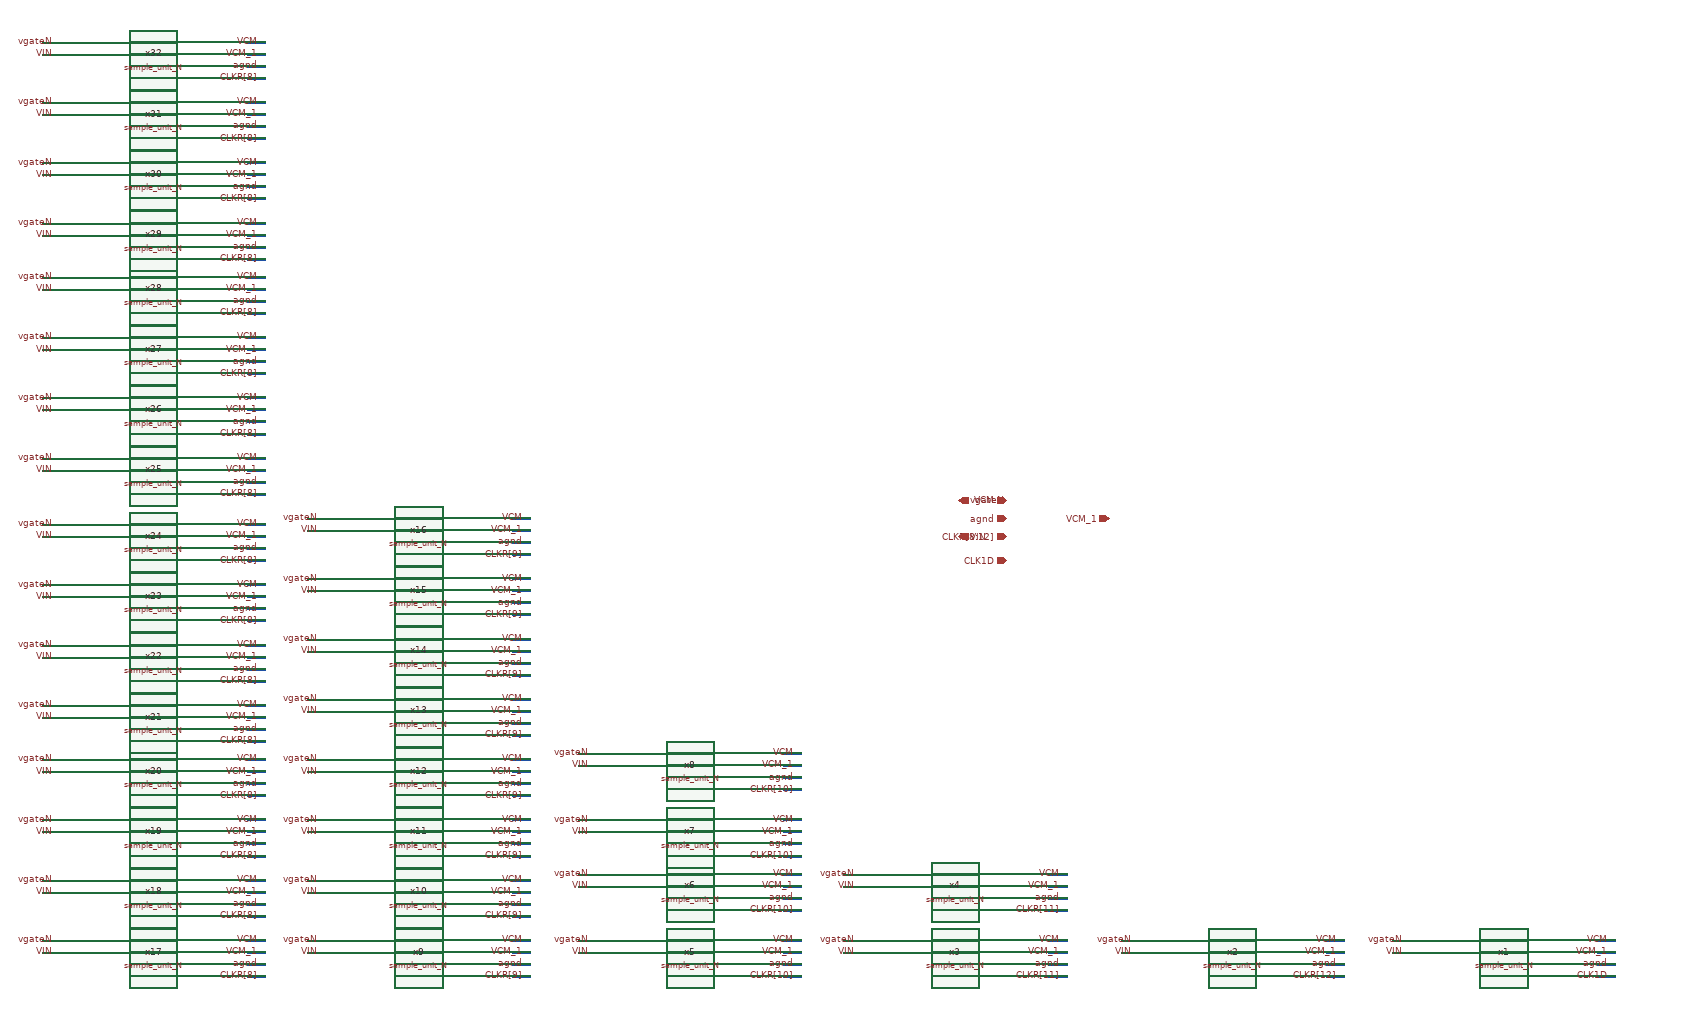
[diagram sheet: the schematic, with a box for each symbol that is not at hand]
v {xschem version=3.1.0 file_version=1.2
}
G {}
K {}
V {}
S {}
E {}
N 1610 -1050 1650 -1050 {
lab=vgateN}
N 1610 -1030 1650 -1030 {
lab=VIN}
N 1950 -1050 1980 -1050 {
lab=VCM}
N 1950 -1030 1980 -1030 {
lab=VCM_1}
N 1950 -1010 1980 -1010 {
lab=agnd}
N 1950 -990 1980 -990 {
lab=CLK1D}
N 1160 -1050 1200 -1050 {
lab=vgateN}
N 1160 -1030 1200 -1030 {
lab=VIN}
N 1500 -1050 1530 -1050 {
lab=VCM}
N 1500 -1030 1530 -1030 {
lab=VCM_1}
N 1500 -1010 1530 -1010 {
lab=agnd}
N 1500 -990 1530 -990 {
lab=CLKR[12]}
N 700 -1050 740 -1050 {
lab=vgateN}
N 700 -1030 740 -1030 {
lab=VIN}
N 1040 -1050 1070 -1050 {
lab=VCM}
N 1040 -1030 1070 -1030 {
lab=VCM_1}
N 1040 -1010 1070 -1010 {
lab=agnd}
N 1040 -990 1070 -990 {
lab=CLKR[11]}
N 700 -1160 740 -1160 {
lab=vgateN}
N 700 -1140 740 -1140 {
lab=VIN}
N 1040 -1160 1070 -1160 {
lab=VCM}
N 1040 -1140 1070 -1140 {
lab=VCM_1}
N 1040 -1120 1070 -1120 {
lab=agnd}
N 1040 -1100 1070 -1100 {
lab=CLKR[11]}
N 260 -1050 300 -1050 {
lab=vgateN}
N 260 -1030 300 -1030 {
lab=VIN}
N 600 -1050 630 -1050 {
lab=VCM}
N 600 -1030 630 -1030 {
lab=VCM_1}
N 600 -1010 630 -1010 {
lab=agnd}
N 600 -990 630 -990 {
lab=CLKR[10]}
N 260 -1160 300 -1160 {
lab=vgateN}
N 260 -1140 300 -1140 {
lab=VIN}
N 600 -1160 630 -1160 {
lab=VCM}
N 600 -1140 630 -1140 {
lab=VCM_1}
N 600 -1120 630 -1120 {
lab=agnd}
N 600 -1100 630 -1100 {
lab=CLKR[10]}
N 260 -1250 300 -1250 {
lab=vgateN}
N 260 -1230 300 -1230 {
lab=VIN}
N 600 -1250 630 -1250 {
lab=VCM}
N 600 -1230 630 -1230 {
lab=VCM_1}
N 600 -1210 630 -1210 {
lab=agnd}
N 600 -1190 630 -1190 {
lab=CLKR[10]}
N 260 -1360 300 -1360 {
lab=vgateN}
N 260 -1340 300 -1340 {
lab=VIN}
N 600 -1360 630 -1360 {
lab=VCM}
N 600 -1340 630 -1340 {
lab=VCM_1}
N 600 -1320 630 -1320 {
lab=agnd}
N 600 -1300 630 -1300 {
lab=CLKR[10]}
N -190 -1050 -150 -1050 {
lab=vgateN}
N -190 -1030 -150 -1030 {
lab=VIN}
N 150 -1050 180 -1050 {
lab=VCM}
N 150 -1030 180 -1030 {
lab=VCM_1}
N 150 -1010 180 -1010 {
lab=agnd}
N 150 -990 180 -990 {
lab=CLKR[9]}
N -190 -1150 -150 -1150 {
lab=vgateN}
N -190 -1130 -150 -1130 {
lab=VIN}
N 150 -1150 180 -1150 {
lab=VCM}
N 150 -1130 180 -1130 {
lab=VCM_1}
N 150 -1110 180 -1110 {
lab=agnd}
N 150 -1090 180 -1090 {
lab=CLKR[9]}
N -190 -1250 -150 -1250 {
lab=vgateN}
N -190 -1230 -150 -1230 {
lab=VIN}
N 150 -1250 180 -1250 {
lab=VCM}
N 150 -1230 180 -1230 {
lab=VCM_1}
N 150 -1210 180 -1210 {
lab=agnd}
N 150 -1190 180 -1190 {
lab=CLKR[9]}
N -190 -1350 -150 -1350 {
lab=vgateN}
N -190 -1330 -150 -1330 {
lab=VIN}
N 150 -1350 180 -1350 {
lab=VCM}
N 150 -1330 180 -1330 {
lab=VCM_1}
N 150 -1310 180 -1310 {
lab=agnd}
N 150 -1290 180 -1290 {
lab=CLKR[9]}
N -190 -1450 -150 -1450 {
lab=vgateN}
N -190 -1430 -150 -1430 {
lab=VIN}
N 150 -1450 180 -1450 {
lab=VCM}
N 150 -1430 180 -1430 {
lab=VCM_1}
N 150 -1410 180 -1410 {
lab=agnd}
N 150 -1390 180 -1390 {
lab=CLKR[9]}
N -190 -1550 -150 -1550 {
lab=vgateN}
N -190 -1530 -150 -1530 {
lab=VIN}
N 150 -1550 180 -1550 {
lab=VCM}
N 150 -1530 180 -1530 {
lab=VCM_1}
N 150 -1510 180 -1510 {
lab=agnd}
N 150 -1490 180 -1490 {
lab=CLKR[9]}
N -190 -1650 -150 -1650 {
lab=vgateN}
N -190 -1630 -150 -1630 {
lab=VIN}
N 150 -1650 180 -1650 {
lab=VCM}
N 150 -1630 180 -1630 {
lab=VCM_1}
N 150 -1610 180 -1610 {
lab=agnd}
N 150 -1590 180 -1590 {
lab=CLKR[9]}
N -190 -1750 -150 -1750 {
lab=vgateN}
N -190 -1730 -150 -1730 {
lab=VIN}
N 150 -1750 180 -1750 {
lab=VCM}
N 150 -1730 180 -1730 {
lab=VCM_1}
N 150 -1710 180 -1710 {
lab=agnd}
N 150 -1690 180 -1690 {
lab=CLKR[9]}
N -630 -1050 -590 -1050 {
lab=vgateN}
N -630 -1030 -590 -1030 {
lab=VIN}
N -290 -1050 -260 -1050 {
lab=VCM}
N -290 -1030 -260 -1030 {
lab=VCM_1}
N -290 -1010 -260 -1010 {
lab=agnd}
N -290 -990 -260 -990 {
lab=CLKR[9]}
N -630 -1150 -590 -1150 {
lab=vgateN}
N -630 -1130 -590 -1130 {
lab=VIN}
N -290 -1150 -260 -1150 {
lab=VCM}
N -290 -1130 -260 -1130 {
lab=VCM_1}
N -290 -1110 -260 -1110 {
lab=agnd}
N -290 -1090 -260 -1090 {
lab=CLKR[9]}
N -630 -1250 -590 -1250 {
lab=vgateN}
N -630 -1230 -590 -1230 {
lab=VIN}
N -290 -1250 -260 -1250 {
lab=VCM}
N -290 -1230 -260 -1230 {
lab=VCM_1}
N -290 -1210 -260 -1210 {
lab=agnd}
N -290 -1190 -260 -1190 {
lab=CLKR[9]}
N -630 -1350 -590 -1350 {
lab=vgateN}
N -630 -1330 -590 -1330 {
lab=VIN}
N -290 -1350 -260 -1350 {
lab=VCM}
N -290 -1330 -260 -1330 {
lab=VCM_1}
N -290 -1310 -260 -1310 {
lab=agnd}
N -290 -1290 -260 -1290 {
lab=CLKR[9]}
N -630 -1440 -590 -1440 {
lab=vgateN}
N -630 -1420 -590 -1420 {
lab=VIN}
N -290 -1440 -260 -1440 {
lab=VCM}
N -290 -1420 -260 -1420 {
lab=VCM_1}
N -290 -1400 -260 -1400 {
lab=agnd}
N -290 -1380 -260 -1380 {
lab=CLKR[9]}
N -630 -1540 -590 -1540 {
lab=vgateN}
N -630 -1520 -590 -1520 {
lab=VIN}
N -290 -1540 -260 -1540 {
lab=VCM}
N -290 -1520 -260 -1520 {
lab=VCM_1}
N -290 -1500 -260 -1500 {
lab=agnd}
N -290 -1480 -260 -1480 {
lab=CLKR[9]}
N -630 -1640 -590 -1640 {
lab=vgateN}
N -630 -1620 -590 -1620 {
lab=VIN}
N -290 -1640 -260 -1640 {
lab=VCM}
N -290 -1620 -260 -1620 {
lab=VCM_1}
N -290 -1600 -260 -1600 {
lab=agnd}
N -290 -1580 -260 -1580 {
lab=CLKR[9]}
N -630 -1740 -590 -1740 {
lab=vgateN}
N -630 -1720 -590 -1720 {
lab=VIN}
N -290 -1740 -260 -1740 {
lab=VCM}
N -290 -1720 -260 -1720 {
lab=VCM_1}
N -290 -1700 -260 -1700 {
lab=agnd}
N -290 -1680 -260 -1680 {
lab=CLKR[9]}
N -630 -1850 -590 -1850 {
lab=vgateN}
N -630 -1830 -590 -1830 {
lab=VIN}
N -290 -1850 -260 -1850 {
lab=VCM}
N -290 -1830 -260 -1830 {
lab=VCM_1}
N -290 -1810 -260 -1810 {
lab=agnd}
N -290 -1790 -260 -1790 {
lab=CLKR[9]}
N -630 -1950 -590 -1950 {
lab=vgateN}
N -630 -1930 -590 -1930 {
lab=VIN}
N -290 -1950 -260 -1950 {
lab=VCM}
N -290 -1930 -260 -1930 {
lab=VCM_1}
N -290 -1910 -260 -1910 {
lab=agnd}
N -290 -1890 -260 -1890 {
lab=CLKR[9]}
N -630 -2050 -590 -2050 {
lab=vgateN}
N -630 -2030 -590 -2030 {
lab=VIN}
N -290 -2050 -260 -2050 {
lab=VCM}
N -290 -2030 -260 -2030 {
lab=VCM_1}
N -290 -2010 -260 -2010 {
lab=agnd}
N -290 -1990 -260 -1990 {
lab=CLKR[9]}
N -630 -2150 -590 -2150 {
lab=vgateN}
N -630 -2130 -590 -2130 {
lab=VIN}
N -290 -2150 -260 -2150 {
lab=VCM}
N -290 -2130 -260 -2130 {
lab=VCM_1}
N -290 -2110 -260 -2110 {
lab=agnd}
N -290 -2090 -260 -2090 {
lab=CLKR[9]}
N -630 -2240 -590 -2240 {
lab=vgateN}
N -630 -2220 -590 -2220 {
lab=VIN}
N -290 -2240 -260 -2240 {
lab=VCM}
N -290 -2220 -260 -2220 {
lab=VCM_1}
N -290 -2200 -260 -2200 {
lab=agnd}
N -290 -2180 -260 -2180 {
lab=CLKR[9]}
N -630 -2340 -590 -2340 {
lab=vgateN}
N -630 -2320 -590 -2320 {
lab=VIN}
N -290 -2340 -260 -2340 {
lab=VCM}
N -290 -2320 -260 -2320 {
lab=VCM_1}
N -290 -2300 -260 -2300 {
lab=agnd}
N -290 -2280 -260 -2280 {
lab=CLKR[9]}
N -630 -2440 -590 -2440 {
lab=vgateN}
N -630 -2420 -590 -2420 {
lab=VIN}
N -290 -2440 -260 -2440 {
lab=VCM}
N -290 -2420 -260 -2420 {
lab=VCM_1}
N -290 -2400 -260 -2400 {
lab=agnd}
N -290 -2380 -260 -2380 {
lab=CLKR[9]}
N -630 -2540 -590 -2540 {
lab=vgateN}
N -630 -2520 -590 -2520 {
lab=VIN}
N -290 -2540 -260 -2540 {
lab=VCM}
N -290 -2520 -260 -2520 {
lab=VCM_1}
N -290 -2500 -260 -2500 {
lab=agnd}
N -290 -2480 -260 -2480 {
lab=CLKR[9]}
C {/home/yihengfu/openmpw/tools-dev/sample_unit_N.sym} 1800 -1020 0 0 {name=x1}
C {lab_pin.sym} 1970 -1050 0 0 {name=p1 sig_type=std_logic lab=VCM}
C {lab_pin.sym} 1970 -1030 0 0 {name=p2 sig_type=std_logic lab=VCM_1}
C {lab_pin.sym} 1970 -1010 0 0 {name=p3 sig_type=std_logic lab=agnd}
C {lab_pin.sym} 1970 -990 0 0 {name=p4 sig_type=std_logic lab=CLK1D}
C {lab_pin.sym} 1630 -1050 0 0 {name=p5 sig_type=std_logic lab=vgateN}
C {lab_pin.sym} 1630 -1030 0 0 {name=p6 sig_type=std_logic lab=VIN}
C {/home/yihengfu/openmpw/tools-dev/sample_unit_N.sym} 1350 -1020 0 0 {name=x2}
C {lab_pin.sym} 1520 -1050 0 0 {name=p7 sig_type=std_logic lab=VCM}
C {lab_pin.sym} 1520 -1030 0 0 {name=p8 sig_type=std_logic lab=VCM_1}
C {lab_pin.sym} 1520 -1010 0 0 {name=p9 sig_type=std_logic lab=agnd}
C {lab_pin.sym} 1520 -990 0 0 {name=p10 sig_type=std_logic lab=CLKR[12]}
C {lab_pin.sym} 1180 -1050 0 0 {name=p11 sig_type=std_logic lab=vgateN}
C {lab_pin.sym} 1180 -1030 0 0 {name=p12 sig_type=std_logic lab=VIN}
C {/home/yihengfu/openmpw/tools-dev/sample_unit_N.sym} 890 -1020 0 0 {name=x3}
C {lab_pin.sym} 1060 -1050 0 0 {name=p13 sig_type=std_logic lab=VCM}
C {lab_pin.sym} 1060 -1030 0 0 {name=p14 sig_type=std_logic lab=VCM_1}
C {lab_pin.sym} 1060 -1010 0 0 {name=p15 sig_type=std_logic lab=agnd}
C {lab_pin.sym} 1060 -990 0 0 {name=p16 sig_type=std_logic lab=CLKR[11]}
C {lab_pin.sym} 720 -1050 0 0 {name=p17 sig_type=std_logic lab=vgateN}
C {lab_pin.sym} 720 -1030 0 0 {name=p18 sig_type=std_logic lab=VIN}
C {/home/yihengfu/openmpw/tools-dev/sample_unit_N.sym} 890 -1130 0 0 {name=x4}
C {lab_pin.sym} 1060 -1160 0 0 {name=p19 sig_type=std_logic lab=VCM}
C {lab_pin.sym} 1060 -1140 0 0 {name=p20 sig_type=std_logic lab=VCM_1}
C {lab_pin.sym} 1060 -1120 0 0 {name=p21 sig_type=std_logic lab=agnd}
C {lab_pin.sym} 1060 -1100 0 0 {name=p22 sig_type=std_logic lab=CLKR[11]}
C {lab_pin.sym} 720 -1160 0 0 {name=p23 sig_type=std_logic lab=vgateN}
C {lab_pin.sym} 720 -1140 0 0 {name=p24 sig_type=std_logic lab=VIN}
C {/home/yihengfu/openmpw/tools-dev/sample_unit_N.sym} 450 -1020 0 0 {name=x5}
C {lab_pin.sym} 620 -1050 0 0 {name=p25 sig_type=std_logic lab=VCM}
C {lab_pin.sym} 620 -1030 0 0 {name=p26 sig_type=std_logic lab=VCM_1}
C {lab_pin.sym} 620 -1010 0 0 {name=p27 sig_type=std_logic lab=agnd}
C {lab_pin.sym} 620 -990 0 0 {name=p28 sig_type=std_logic lab=CLKR[10]}
C {lab_pin.sym} 280 -1050 0 0 {name=p29 sig_type=std_logic lab=vgateN}
C {lab_pin.sym} 280 -1030 0 0 {name=p30 sig_type=std_logic lab=VIN}
C {/home/yihengfu/openmpw/tools-dev/sample_unit_N.sym} 450 -1130 0 0 {name=x6}
C {lab_pin.sym} 620 -1160 0 0 {name=p31 sig_type=std_logic lab=VCM}
C {lab_pin.sym} 620 -1140 0 0 {name=p32 sig_type=std_logic lab=VCM_1}
C {lab_pin.sym} 620 -1120 0 0 {name=p33 sig_type=std_logic lab=agnd}
C {lab_pin.sym} 620 -1100 0 0 {name=p34 sig_type=std_logic lab=CLKR[10]}
C {lab_pin.sym} 280 -1160 0 0 {name=p35 sig_type=std_logic lab=vgateN}
C {lab_pin.sym} 280 -1140 0 0 {name=p36 sig_type=std_logic lab=VIN}
C {/home/yihengfu/openmpw/tools-dev/sample_unit_N.sym} 450 -1220 0 0 {name=x7}
C {lab_pin.sym} 620 -1250 0 0 {name=p37 sig_type=std_logic lab=VCM}
C {lab_pin.sym} 620 -1230 0 0 {name=p38 sig_type=std_logic lab=VCM_1}
C {lab_pin.sym} 620 -1210 0 0 {name=p39 sig_type=std_logic lab=agnd}
C {lab_pin.sym} 620 -1190 0 0 {name=p40 sig_type=std_logic lab=CLKR[10]}
C {lab_pin.sym} 280 -1250 0 0 {name=p41 sig_type=std_logic lab=vgateN}
C {lab_pin.sym} 280 -1230 0 0 {name=p42 sig_type=std_logic lab=VIN}
C {/home/yihengfu/openmpw/tools-dev/sample_unit_N.sym} 450 -1330 0 0 {name=x8}
C {lab_pin.sym} 620 -1360 0 0 {name=p43 sig_type=std_logic lab=VCM}
C {lab_pin.sym} 620 -1340 0 0 {name=p44 sig_type=std_logic lab=VCM_1}
C {lab_pin.sym} 620 -1320 0 0 {name=p45 sig_type=std_logic lab=agnd}
C {lab_pin.sym} 620 -1300 0 0 {name=p46 sig_type=std_logic lab=CLKR[10]}
C {lab_pin.sym} 280 -1360 0 0 {name=p47 sig_type=std_logic lab=vgateN}
C {lab_pin.sym} 280 -1340 0 0 {name=p48 sig_type=std_logic lab=VIN}
C {/home/yihengfu/openmpw/tools-dev/sample_unit_N.sym} 0 -1020 0 0 {name=x9}
C {lab_pin.sym} 170 -1050 0 0 {name=p49 sig_type=std_logic lab=VCM}
C {lab_pin.sym} 170 -1030 0 0 {name=p50 sig_type=std_logic lab=VCM_1}
C {lab_pin.sym} 170 -1010 0 0 {name=p51 sig_type=std_logic lab=agnd}
C {lab_pin.sym} 170 -990 0 0 {name=p52 sig_type=std_logic lab=CLKR[9]}
C {lab_pin.sym} -170 -1050 0 0 {name=p53 sig_type=std_logic lab=vgateN}
C {lab_pin.sym} -170 -1030 0 0 {name=p54 sig_type=std_logic lab=VIN}
C {/home/yihengfu/openmpw/tools-dev/sample_unit_N.sym} 0 -1120 0 0 {name=x10}
C {lab_pin.sym} 170 -1150 0 0 {name=p55 sig_type=std_logic lab=VCM}
C {lab_pin.sym} 170 -1130 0 0 {name=p56 sig_type=std_logic lab=VCM_1}
C {lab_pin.sym} 170 -1110 0 0 {name=p57 sig_type=std_logic lab=agnd}
C {lab_pin.sym} 170 -1090 0 0 {name=p58 sig_type=std_logic lab=CLKR[9]}
C {lab_pin.sym} -170 -1150 0 0 {name=p59 sig_type=std_logic lab=vgateN}
C {lab_pin.sym} -170 -1130 0 0 {name=p60 sig_type=std_logic lab=VIN}
C {/home/yihengfu/openmpw/tools-dev/sample_unit_N.sym} 0 -1220 0 0 {name=x11}
C {lab_pin.sym} 170 -1250 0 0 {name=p61 sig_type=std_logic lab=VCM}
C {lab_pin.sym} 170 -1230 0 0 {name=p62 sig_type=std_logic lab=VCM_1}
C {lab_pin.sym} 170 -1210 0 0 {name=p63 sig_type=std_logic lab=agnd}
C {lab_pin.sym} 170 -1190 0 0 {name=p64 sig_type=std_logic lab=CLKR[9]}
C {lab_pin.sym} -170 -1250 0 0 {name=p65 sig_type=std_logic lab=vgateN}
C {lab_pin.sym} -170 -1230 0 0 {name=p66 sig_type=std_logic lab=VIN}
C {/home/yihengfu/openmpw/tools-dev/sample_unit_N.sym} 0 -1320 0 0 {name=x12}
C {lab_pin.sym} 170 -1350 0 0 {name=p67 sig_type=std_logic lab=VCM}
C {lab_pin.sym} 170 -1330 0 0 {name=p68 sig_type=std_logic lab=VCM_1}
C {lab_pin.sym} 170 -1310 0 0 {name=p69 sig_type=std_logic lab=agnd}
C {lab_pin.sym} 170 -1290 0 0 {name=p70 sig_type=std_logic lab=CLKR[9]}
C {lab_pin.sym} -170 -1350 0 0 {name=p71 sig_type=std_logic lab=vgateN}
C {lab_pin.sym} -170 -1330 0 0 {name=p72 sig_type=std_logic lab=VIN}
C {/home/yihengfu/openmpw/tools-dev/sample_unit_N.sym} 0 -1420 0 0 {name=x13}
C {lab_pin.sym} 170 -1450 0 0 {name=p73 sig_type=std_logic lab=VCM}
C {lab_pin.sym} 170 -1430 0 0 {name=p74 sig_type=std_logic lab=VCM_1}
C {lab_pin.sym} 170 -1410 0 0 {name=p75 sig_type=std_logic lab=agnd}
C {lab_pin.sym} 170 -1390 0 0 {name=p76 sig_type=std_logic lab=CLKR[9]}
C {lab_pin.sym} -170 -1450 0 0 {name=p77 sig_type=std_logic lab=vgateN}
C {lab_pin.sym} -170 -1430 0 0 {name=p78 sig_type=std_logic lab=VIN}
C {/home/yihengfu/openmpw/tools-dev/sample_unit_N.sym} 0 -1520 0 0 {name=x14}
C {lab_pin.sym} 170 -1550 0 0 {name=p79 sig_type=std_logic lab=VCM}
C {lab_pin.sym} 170 -1530 0 0 {name=p80 sig_type=std_logic lab=VCM_1}
C {lab_pin.sym} 170 -1510 0 0 {name=p81 sig_type=std_logic lab=agnd}
C {lab_pin.sym} 170 -1490 0 0 {name=p82 sig_type=std_logic lab=CLKR[9]}
C {lab_pin.sym} -170 -1550 0 0 {name=p83 sig_type=std_logic lab=vgateN}
C {lab_pin.sym} -170 -1530 0 0 {name=p84 sig_type=std_logic lab=VIN}
C {/home/yihengfu/openmpw/tools-dev/sample_unit_N.sym} 0 -1620 0 0 {name=x15}
C {lab_pin.sym} 170 -1650 0 0 {name=p85 sig_type=std_logic lab=VCM}
C {lab_pin.sym} 170 -1630 0 0 {name=p86 sig_type=std_logic lab=VCM_1}
C {lab_pin.sym} 170 -1610 0 0 {name=p87 sig_type=std_logic lab=agnd}
C {lab_pin.sym} 170 -1590 0 0 {name=p88 sig_type=std_logic lab=CLKR[9]}
C {lab_pin.sym} -170 -1650 0 0 {name=p89 sig_type=std_logic lab=vgateN}
C {lab_pin.sym} -170 -1630 0 0 {name=p90 sig_type=std_logic lab=VIN}
C {/home/yihengfu/openmpw/tools-dev/sample_unit_N.sym} 0 -1720 0 0 {name=x16}
C {lab_pin.sym} 170 -1750 0 0 {name=p91 sig_type=std_logic lab=VCM}
C {lab_pin.sym} 170 -1730 0 0 {name=p92 sig_type=std_logic lab=VCM_1}
C {lab_pin.sym} 170 -1710 0 0 {name=p93 sig_type=std_logic lab=agnd}
C {lab_pin.sym} 170 -1690 0 0 {name=p94 sig_type=std_logic lab=CLKR[9]}
C {lab_pin.sym} -170 -1750 0 0 {name=p95 sig_type=std_logic lab=vgateN}
C {lab_pin.sym} -170 -1730 0 0 {name=p96 sig_type=std_logic lab=VIN}
C {/home/yihengfu/openmpw/tools-dev/sample_unit_N.sym} -440 -1020 0 0 {name=x17}
C {lab_pin.sym} -270 -1050 0 0 {name=p97 sig_type=std_logic lab=VCM}
C {lab_pin.sym} -270 -1030 0 0 {name=p98 sig_type=std_logic lab=VCM_1}
C {lab_pin.sym} -270 -1010 0 0 {name=p99 sig_type=std_logic lab=agnd}
C {lab_pin.sym} -270 -990 0 0 {name=p100 sig_type=std_logic lab=CLKR[8]}
C {lab_pin.sym} -610 -1050 0 0 {name=p101 sig_type=std_logic lab=vgateN}
C {lab_pin.sym} -610 -1030 0 0 {name=p102 sig_type=std_logic lab=VIN}
C {/home/yihengfu/openmpw/tools-dev/sample_unit_N.sym} -440 -1120 0 0 {name=x18}
C {lab_pin.sym} -270 -1150 0 0 {name=p103 sig_type=std_logic lab=VCM}
C {lab_pin.sym} -270 -1130 0 0 {name=p104 sig_type=std_logic lab=VCM_1}
C {lab_pin.sym} -270 -1110 0 0 {name=p105 sig_type=std_logic lab=agnd}
C {lab_pin.sym} -270 -1090 0 0 {name=p106 sig_type=std_logic lab=CLKR[8]}
C {lab_pin.sym} -610 -1150 0 0 {name=p107 sig_type=std_logic lab=vgateN}
C {lab_pin.sym} -610 -1130 0 0 {name=p108 sig_type=std_logic lab=VIN}
C {/home/yihengfu/openmpw/tools-dev/sample_unit_N.sym} -440 -1220 0 0 {name=x19}
C {lab_pin.sym} -270 -1250 0 0 {name=p109 sig_type=std_logic lab=VCM}
C {lab_pin.sym} -270 -1230 0 0 {name=p110 sig_type=std_logic lab=VCM_1}
C {lab_pin.sym} -270 -1210 0 0 {name=p111 sig_type=std_logic lab=agnd}
C {lab_pin.sym} -270 -1190 0 0 {name=p112 sig_type=std_logic lab=CLKR[8]}
C {lab_pin.sym} -610 -1250 0 0 {name=p113 sig_type=std_logic lab=vgateN}
C {lab_pin.sym} -610 -1230 0 0 {name=p114 sig_type=std_logic lab=VIN}
C {/home/yihengfu/openmpw/tools-dev/sample_unit_N.sym} -440 -1320 0 0 {name=x20}
C {lab_pin.sym} -270 -1350 0 0 {name=p115 sig_type=std_logic lab=VCM}
C {lab_pin.sym} -270 -1330 0 0 {name=p116 sig_type=std_logic lab=VCM_1}
C {lab_pin.sym} -270 -1310 0 0 {name=p117 sig_type=std_logic lab=agnd}
C {lab_pin.sym} -270 -1290 0 0 {name=p118 sig_type=std_logic lab=CLKR[8]}
C {lab_pin.sym} -610 -1350 0 0 {name=p119 sig_type=std_logic lab=vgateN}
C {lab_pin.sym} -610 -1330 0 0 {name=p120 sig_type=std_logic lab=VIN}
C {/home/yihengfu/openmpw/tools-dev/sample_unit_N.sym} -440 -1410 0 0 {name=x21}
C {lab_pin.sym} -270 -1440 0 0 {name=p121 sig_type=std_logic lab=VCM}
C {lab_pin.sym} -270 -1420 0 0 {name=p122 sig_type=std_logic lab=VCM_1}
C {lab_pin.sym} -270 -1400 0 0 {name=p123 sig_type=std_logic lab=agnd}
C {lab_pin.sym} -270 -1380 0 0 {name=p124 sig_type=std_logic lab=CLKR[8]}
C {lab_pin.sym} -610 -1440 0 0 {name=p125 sig_type=std_logic lab=vgateN}
C {lab_pin.sym} -610 -1420 0 0 {name=p126 sig_type=std_logic lab=VIN}
C {/home/yihengfu/openmpw/tools-dev/sample_unit_N.sym} -440 -1510 0 0 {name=x22}
C {lab_pin.sym} -270 -1540 0 0 {name=p127 sig_type=std_logic lab=VCM}
C {lab_pin.sym} -270 -1520 0 0 {name=p128 sig_type=std_logic lab=VCM_1}
C {lab_pin.sym} -270 -1500 0 0 {name=p129 sig_type=std_logic lab=agnd}
C {lab_pin.sym} -270 -1480 0 0 {name=p130 sig_type=std_logic lab=CLKR[8]}
C {lab_pin.sym} -610 -1540 0 0 {name=p131 sig_type=std_logic lab=vgateN}
C {lab_pin.sym} -610 -1520 0 0 {name=p132 sig_type=std_logic lab=VIN}
C {/home/yihengfu/openmpw/tools-dev/sample_unit_N.sym} -440 -1610 0 0 {name=x23}
C {lab_pin.sym} -270 -1640 0 0 {name=p133 sig_type=std_logic lab=VCM}
C {lab_pin.sym} -270 -1620 0 0 {name=p134 sig_type=std_logic lab=VCM_1}
C {lab_pin.sym} -270 -1600 0 0 {name=p135 sig_type=std_logic lab=agnd}
C {lab_pin.sym} -270 -1580 0 0 {name=p136 sig_type=std_logic lab=CLKR[8]}
C {lab_pin.sym} -610 -1640 0 0 {name=p137 sig_type=std_logic lab=vgateN}
C {lab_pin.sym} -610 -1620 0 0 {name=p138 sig_type=std_logic lab=VIN}
C {/home/yihengfu/openmpw/tools-dev/sample_unit_N.sym} -440 -1710 0 0 {name=x24}
C {lab_pin.sym} -270 -1740 0 0 {name=p139 sig_type=std_logic lab=VCM}
C {lab_pin.sym} -270 -1720 0 0 {name=p140 sig_type=std_logic lab=VCM_1}
C {lab_pin.sym} -270 -1700 0 0 {name=p141 sig_type=std_logic lab=agnd}
C {lab_pin.sym} -270 -1680 0 0 {name=p142 sig_type=std_logic lab=CLKR[8]}
C {lab_pin.sym} -610 -1740 0 0 {name=p143 sig_type=std_logic lab=vgateN}
C {lab_pin.sym} -610 -1720 0 0 {name=p144 sig_type=std_logic lab=VIN}
C {/home/yihengfu/openmpw/tools-dev/sample_unit_N.sym} -440 -1820 0 0 {name=x25}
C {lab_pin.sym} -270 -1850 0 0 {name=p145 sig_type=std_logic lab=VCM}
C {lab_pin.sym} -270 -1830 0 0 {name=p146 sig_type=std_logic lab=VCM_1}
C {lab_pin.sym} -270 -1810 0 0 {name=p147 sig_type=std_logic lab=agnd}
C {lab_pin.sym} -270 -1790 0 0 {name=p148 sig_type=std_logic lab=CLKR[8]}
C {lab_pin.sym} -610 -1850 0 0 {name=p149 sig_type=std_logic lab=vgateN}
C {lab_pin.sym} -610 -1830 0 0 {name=p150 sig_type=std_logic lab=VIN}
C {/home/yihengfu/openmpw/tools-dev/sample_unit_N.sym} -440 -1920 0 0 {name=x26}
C {lab_pin.sym} -270 -1950 0 0 {name=p151 sig_type=std_logic lab=VCM}
C {lab_pin.sym} -270 -1930 0 0 {name=p152 sig_type=std_logic lab=VCM_1}
C {lab_pin.sym} -270 -1910 0 0 {name=p153 sig_type=std_logic lab=agnd}
C {lab_pin.sym} -270 -1890 0 0 {name=p154 sig_type=std_logic lab=CLKR[8]}
C {lab_pin.sym} -610 -1950 0 0 {name=p155 sig_type=std_logic lab=vgateN}
C {lab_pin.sym} -610 -1930 0 0 {name=p156 sig_type=std_logic lab=VIN}
C {/home/yihengfu/openmpw/tools-dev/sample_unit_N.sym} -440 -2020 0 0 {name=x27}
C {lab_pin.sym} -270 -2050 0 0 {name=p157 sig_type=std_logic lab=VCM}
C {lab_pin.sym} -270 -2030 0 0 {name=p158 sig_type=std_logic lab=VCM_1}
C {lab_pin.sym} -270 -2010 0 0 {name=p159 sig_type=std_logic lab=agnd}
C {lab_pin.sym} -270 -1990 0 0 {name=p160 sig_type=std_logic lab=CLKR[8]}
C {lab_pin.sym} -610 -2050 0 0 {name=p161 sig_type=std_logic lab=vgateN}
C {lab_pin.sym} -610 -2030 0 0 {name=p162 sig_type=std_logic lab=VIN}
C {/home/yihengfu/openmpw/tools-dev/sample_unit_N.sym} -440 -2120 0 0 {name=x28}
C {lab_pin.sym} -270 -2150 0 0 {name=p163 sig_type=std_logic lab=VCM}
C {lab_pin.sym} -270 -2130 0 0 {name=p164 sig_type=std_logic lab=VCM_1}
C {lab_pin.sym} -270 -2110 0 0 {name=p165 sig_type=std_logic lab=agnd}
C {lab_pin.sym} -270 -2090 0 0 {name=p166 sig_type=std_logic lab=CLKR[8]}
C {lab_pin.sym} -610 -2150 0 0 {name=p167 sig_type=std_logic lab=vgateN}
C {lab_pin.sym} -610 -2130 0 0 {name=p168 sig_type=std_logic lab=VIN}
C {/home/yihengfu/openmpw/tools-dev/sample_unit_N.sym} -440 -2210 0 0 {name=x29}
C {lab_pin.sym} -270 -2240 0 0 {name=p169 sig_type=std_logic lab=VCM}
C {lab_pin.sym} -270 -2220 0 0 {name=p170 sig_type=std_logic lab=VCM_1}
C {lab_pin.sym} -270 -2200 0 0 {name=p171 sig_type=std_logic lab=agnd}
C {lab_pin.sym} -270 -2180 0 0 {name=p172 sig_type=std_logic lab=CLKR[8]}
C {lab_pin.sym} -610 -2240 0 0 {name=p173 sig_type=std_logic lab=vgateN}
C {lab_pin.sym} -610 -2220 0 0 {name=p174 sig_type=std_logic lab=VIN}
C {/home/yihengfu/openmpw/tools-dev/sample_unit_N.sym} -440 -2310 0 0 {name=x30}
C {lab_pin.sym} -270 -2340 0 0 {name=p175 sig_type=std_logic lab=VCM}
C {lab_pin.sym} -270 -2320 0 0 {name=p176 sig_type=std_logic lab=VCM_1}
C {lab_pin.sym} -270 -2300 0 0 {name=p177 sig_type=std_logic lab=agnd}
C {lab_pin.sym} -270 -2280 0 0 {name=p178 sig_type=std_logic lab=CLKR[8]}
C {lab_pin.sym} -610 -2340 0 0 {name=p179 sig_type=std_logic lab=vgateN}
C {lab_pin.sym} -610 -2320 0 0 {name=p180 sig_type=std_logic lab=VIN}
C {/home/yihengfu/openmpw/tools-dev/sample_unit_N.sym} -440 -2410 0 0 {name=x31}
C {lab_pin.sym} -270 -2440 0 0 {name=p181 sig_type=std_logic lab=VCM}
C {lab_pin.sym} -270 -2420 0 0 {name=p182 sig_type=std_logic lab=VCM_1}
C {lab_pin.sym} -270 -2400 0 0 {name=p183 sig_type=std_logic lab=agnd}
C {lab_pin.sym} -270 -2380 0 0 {name=p184 sig_type=std_logic lab=CLKR[8]}
C {lab_pin.sym} -610 -2440 0 0 {name=p185 sig_type=std_logic lab=vgateN}
C {lab_pin.sym} -610 -2420 0 0 {name=p186 sig_type=std_logic lab=VIN}
C {/home/yihengfu/openmpw/tools-dev/sample_unit_N.sym} -440 -2510 0 0 {name=x32}
C {lab_pin.sym} -270 -2540 0 0 {name=p187 sig_type=std_logic lab=VCM}
C {lab_pin.sym} -270 -2520 0 0 {name=p188 sig_type=std_logic lab=VCM_1}
C {lab_pin.sym} -270 -2500 0 0 {name=p189 sig_type=std_logic lab=agnd}
C {lab_pin.sym} -270 -2480 0 0 {name=p190 sig_type=std_logic lab=CLKR[8]}
C {lab_pin.sym} -610 -2540 0 0 {name=p191 sig_type=std_logic lab=vgateN}
C {lab_pin.sym} -610 -2520 0 0 {name=p192 sig_type=std_logic lab=VIN}
C {ipin.sym} 1140 -1750 0 0 {name=p289 lab=VCM_1}
C {opin.sym} 890 -1780 0 0 {name=p290 lab=vgateN}
C {iopin.sym} 970 -1780 0 0 {name=p291 lab=VCM}
C {iopin.sym} 970 -1750 0 0 {name=p292 lab=agnd}
C {iopin.sym} 970 -1720 0 0 {name=p293 lab=CLKR[8:12]}
C {iopin.sym} 970 -1680 0 0 {name=p294 lab=CLK1D}
C {opin.sym} 890 -1720 0 0 {name=p296 lab=VIN}
